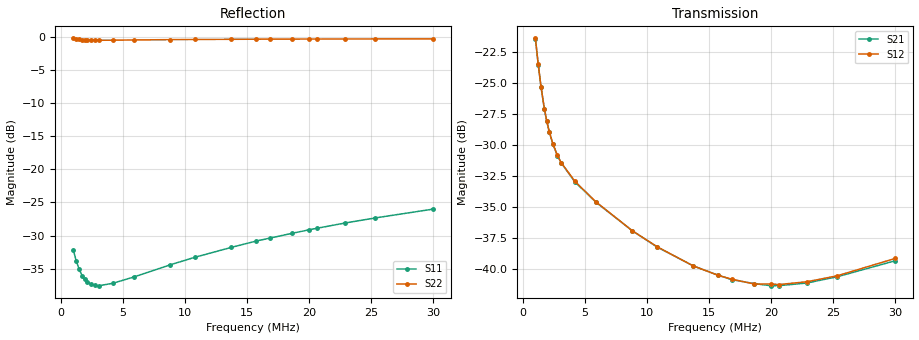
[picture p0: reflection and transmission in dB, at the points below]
! ListType=Log
!!BN140-43 7T #20 TL CM
# MHZ S RI R 50
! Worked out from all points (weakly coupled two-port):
!   101 points, 1 MHz to 30 MHz, reference 50 ohm
!   highest |S21| = -21.42 dB at 1 MHz (marker M1); lowest = -41.4 dB at 19.95 MHz (marker M2)
!   lowest |S11| = -37.5 dB at 3.072 MHz (marker M3), VSWR 1.03, Z = 49.7 + j1.3 ohm
!   |S11| at or under -10 dB: start of sweep to end of sweep
!   |S22| runs from -0.6 to -0.3 dB; largest |S21 - S12| = 0.00035
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1  -0.00314 0.0242  0.00894 -0.0845  0.00905 -0.0848  0.9082 0.3401
1.226386  -0.00254 0.0202  0.0075 -0.0664  0.00756 -0.0666  0.9224 0.2705
1.453729  -0.00244 0.0175  0.00774 -0.0536  0.00781 -0.0537  0.9269 0.2241
1.723215  -0.00256 0.0154  0.00911 -0.0431  0.00914 -0.0434  0.9285 0.1871
1.908328  -0.00269 0.0145  0.0101 -0.0382  0.0102 -0.0384  0.9289 0.1688
2.113327  -0.00271 0.0139  0.011 -0.034  0.0111 -0.0341  0.9293 0.1527
2.421316  -0.00277 0.0133  0.0121 -0.0294  0.0122 -0.0294  0.93 0.1344
2.774191  -0.00265 0.0131  0.0129 -0.0256  0.013 -0.0256  0.9309 0.1188
3.072204  -0.00251 0.013  0.0133 -0.0233  0.0134 -0.0233  0.9318 0.1087
4.172448  -0.00169 0.0137  0.0137 -0.0178  0.0138 -0.0179  0.9358 0.0838
5.862773  3.22e-05 0.0154  0.0129 -0.0134  0.013 -0.0134  0.9414 0.0622
8.817746  0.00362 0.0187  0.0113 -0.00866  0.0114 -0.00853  0.9478 0.0411
10.81396  0.00626 0.0208  0.0105 -0.00629  0.0106 -0.0062  0.9508 0.0317
13.72092  0.0105 0.0235  0.00965 -0.00354  0.0097 -0.00339  0.954 0.0212
15.72057  0.0138 0.0252  0.00924 -0.00186  0.00926 -0.0017  0.9556 0.0153
16.82715  0.0156 0.0259  0.00898 -0.00104  0.00904 -0.000891  0.9564 0.0123
18.63478  0.0188 0.027  0.00871 0.000353  0.00867 0.000495  0.9575 0.00779
19.9465  0.0213 0.0276  0.00846 0.00124  0.00857 0.00145  0.9582 0.00468
20.63659  0.0226 0.0279  0.00838 0.00172  0.00842 0.00194  0.9585 0.00304
22.85344  0.027 0.0285  0.00814 0.00324  0.00819 0.0034  0.9596 -0.0017
25.30843  0.032 0.0286  0.00797 0.00477  0.00794 0.00498  0.9604 -0.00667
30  0.0421 0.0271  0.00762 0.00763  0.0076 0.00798  0.9618 -0.0154
